One B-rep face of a CAD part: STEP entity #681.
In plain terms, the planar face has unit normal (0, 0, 1).
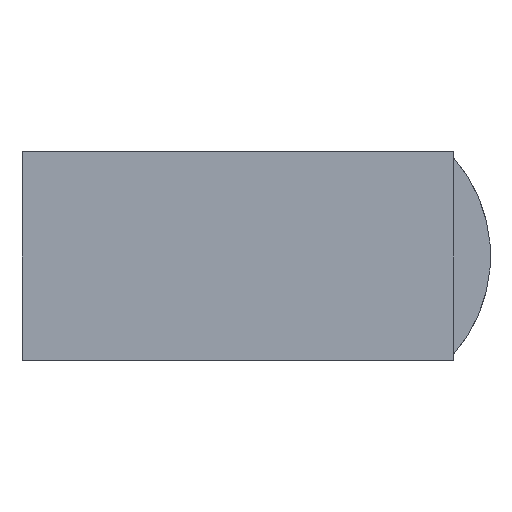
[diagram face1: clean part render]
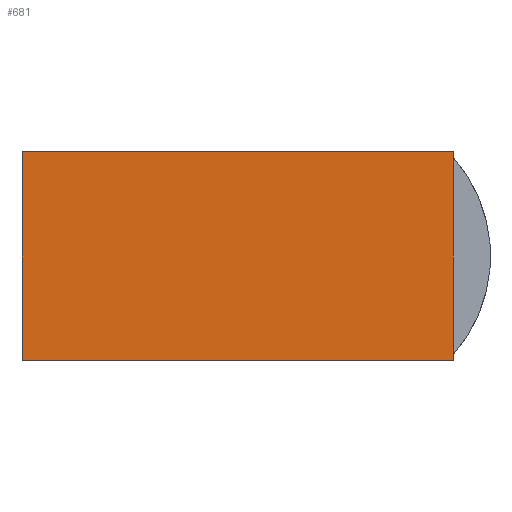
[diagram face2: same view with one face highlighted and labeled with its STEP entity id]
Its self-contained STEP definition (entity closure, numbers rounded to 3 decimals):
#90 = PLANE('',#91);
#91 = AXIS2_PLACEMENT_3D('',#92,#93,#94);
#92 = CARTESIAN_POINT('',(1.4,-20.,-5.));
#93 = DIRECTION('',(1.,0.,-0.));
#94 = DIRECTION('',(0.,0.,1.));
#144 = PLANE('',#145);
#145 = AXIS2_PLACEMENT_3D('',#146,#147,#148);
#146 = CARTESIAN_POINT('',(-1.4,-20.,-5.));
#147 = DIRECTION('',(1.,0.,-0.));
#148 = DIRECTION('',(0.,0.,1.));
#344 = VERTEX_POINT('',#345);
#345 = CARTESIAN_POINT('',(-1.4,-3.7,5.25));
#359 = PLANE('',#360);
#360 = AXIS2_PLACEMENT_3D('',#361,#362,#363);
#361 = CARTESIAN_POINT('',(-2.,-3.7,4.05));
#362 = DIRECTION('',(-0.,1.,0.));
#363 = DIRECTION('',(0.,0.,1.));
#371 = EDGE_CURVE('',#372,#344,#374,.T.);
#372 = VERTEX_POINT('',#373);
#373 = CARTESIAN_POINT('',(-1.4,-9.5,5.25));
#374 = SURFACE_CURVE('',#375,(#379,#386),.PCURVE_S1.);
#375 = LINE('',#376,#377);
#376 = CARTESIAN_POINT('',(-1.4,-14.75,5.25));
#377 = VECTOR('',#378,1.);
#378 = DIRECTION('',(-0.,1.,0.));
#379 = PCURVE('',#144,#380);
#380 = DEFINITIONAL_REPRESENTATION('',(#381),#385);
#381 = LINE('',#382,#383);
#382 = CARTESIAN_POINT('',(10.25,-5.25));
#383 = VECTOR('',#384,1.);
#384 = DIRECTION('',(0.,-1.));
#385 = ( GEOMETRIC_REPRESENTATION_CONTEXT(2) 
PARAMETRIC_REPRESENTATION_CONTEXT() REPRESENTATION_CONTEXT('2D SPACE',''
  ) );
#386 = PCURVE('',#387,#392);
#387 = PLANE('',#388);
#388 = AXIS2_PLACEMENT_3D('',#389,#390,#391);
#389 = CARTESIAN_POINT('',(-2.,-9.5,5.25));
#390 = DIRECTION('',(0.,0.,1.));
#391 = DIRECTION('',(1.,0.,-0.));
#392 = DEFINITIONAL_REPRESENTATION('',(#393),#397);
#393 = LINE('',#394,#395);
#394 = CARTESIAN_POINT('',(0.6,-5.25));
#395 = VECTOR('',#396,1.);
#396 = DIRECTION('',(0.,1.));
#397 = ( GEOMETRIC_REPRESENTATION_CONTEXT(2) 
PARAMETRIC_REPRESENTATION_CONTEXT() REPRESENTATION_CONTEXT('2D SPACE',''
  ) );
#415 = PLANE('',#416);
#416 = AXIS2_PLACEMENT_3D('',#417,#418,#419);
#417 = CARTESIAN_POINT('',(-2.,-9.5,4.05));
#418 = DIRECTION('',(-0.,1.,0.));
#419 = DIRECTION('',(0.,0.,1.));
#507 = EDGE_CURVE('',#372,#508,#510,.T.);
#508 = VERTEX_POINT('',#509);
#509 = CARTESIAN_POINT('',(1.4,-9.5,5.25));
#510 = SURFACE_CURVE('',#511,(#515,#522),.PCURVE_S1.);
#511 = LINE('',#512,#513);
#512 = CARTESIAN_POINT('',(-2.,-9.5,5.25));
#513 = VECTOR('',#514,1.);
#514 = DIRECTION('',(1.,0.,-0.));
#515 = PCURVE('',#415,#516);
#516 = DEFINITIONAL_REPRESENTATION('',(#517),#521);
#517 = LINE('',#518,#519);
#518 = CARTESIAN_POINT('',(1.2,0.));
#519 = VECTOR('',#520,1.);
#520 = DIRECTION('',(0.,1.));
#521 = ( GEOMETRIC_REPRESENTATION_CONTEXT(2) 
PARAMETRIC_REPRESENTATION_CONTEXT() REPRESENTATION_CONTEXT('2D SPACE',''
  ) );
#522 = PCURVE('',#387,#523);
#523 = DEFINITIONAL_REPRESENTATION('',(#524),#528);
#524 = LINE('',#525,#526);
#525 = CARTESIAN_POINT('',(0.,0.));
#526 = VECTOR('',#527,1.);
#527 = DIRECTION('',(1.,0.));
#528 = ( GEOMETRIC_REPRESENTATION_CONTEXT(2) 
PARAMETRIC_REPRESENTATION_CONTEXT() REPRESENTATION_CONTEXT('2D SPACE',''
  ) );
#681 = ADVANCED_FACE('',(#682),#387,.T.);
#682 = FACE_BOUND('',#683,.T.);
#683 = EDGE_LOOP('',(#684,#685,#686,#709));
#684 = ORIENTED_EDGE('',*,*,#371,.F.);
#685 = ORIENTED_EDGE('',*,*,#507,.T.);
#686 = ORIENTED_EDGE('',*,*,#687,.T.);
#687 = EDGE_CURVE('',#508,#688,#690,.T.);
#688 = VERTEX_POINT('',#689);
#689 = CARTESIAN_POINT('',(1.4,-3.7,5.25));
#690 = SURFACE_CURVE('',#691,(#695,#702),.PCURVE_S1.);
#691 = LINE('',#692,#693);
#692 = CARTESIAN_POINT('',(1.4,-14.75,5.25));
#693 = VECTOR('',#694,1.);
#694 = DIRECTION('',(-0.,1.,0.));
#695 = PCURVE('',#387,#696);
#696 = DEFINITIONAL_REPRESENTATION('',(#697),#701);
#697 = LINE('',#698,#699);
#698 = CARTESIAN_POINT('',(3.4,-5.25));
#699 = VECTOR('',#700,1.);
#700 = DIRECTION('',(0.,1.));
#701 = ( GEOMETRIC_REPRESENTATION_CONTEXT(2) 
PARAMETRIC_REPRESENTATION_CONTEXT() REPRESENTATION_CONTEXT('2D SPACE',''
  ) );
#702 = PCURVE('',#90,#703);
#703 = DEFINITIONAL_REPRESENTATION('',(#704),#708);
#704 = LINE('',#705,#706);
#705 = CARTESIAN_POINT('',(10.25,-5.25));
#706 = VECTOR('',#707,1.);
#707 = DIRECTION('',(0.,-1.));
#708 = ( GEOMETRIC_REPRESENTATION_CONTEXT(2) 
PARAMETRIC_REPRESENTATION_CONTEXT() REPRESENTATION_CONTEXT('2D SPACE',''
  ) );
#709 = ORIENTED_EDGE('',*,*,#710,.F.);
#710 = EDGE_CURVE('',#344,#688,#711,.T.);
#711 = SURFACE_CURVE('',#712,(#716,#723),.PCURVE_S1.);
#712 = LINE('',#713,#714);
#713 = CARTESIAN_POINT('',(-2.,-3.7,5.25));
#714 = VECTOR('',#715,1.);
#715 = DIRECTION('',(1.,0.,-0.));
#716 = PCURVE('',#387,#717);
#717 = DEFINITIONAL_REPRESENTATION('',(#718),#722);
#718 = LINE('',#719,#720);
#719 = CARTESIAN_POINT('',(0.,5.8));
#720 = VECTOR('',#721,1.);
#721 = DIRECTION('',(1.,0.));
#722 = ( GEOMETRIC_REPRESENTATION_CONTEXT(2) 
PARAMETRIC_REPRESENTATION_CONTEXT() REPRESENTATION_CONTEXT('2D SPACE',''
  ) );
#723 = PCURVE('',#359,#724);
#724 = DEFINITIONAL_REPRESENTATION('',(#725),#729);
#725 = LINE('',#726,#727);
#726 = CARTESIAN_POINT('',(1.2,0.));
#727 = VECTOR('',#728,1.);
#728 = DIRECTION('',(0.,1.));
#729 = ( GEOMETRIC_REPRESENTATION_CONTEXT(2) 
PARAMETRIC_REPRESENTATION_CONTEXT() REPRESENTATION_CONTEXT('2D SPACE',''
  ) );
